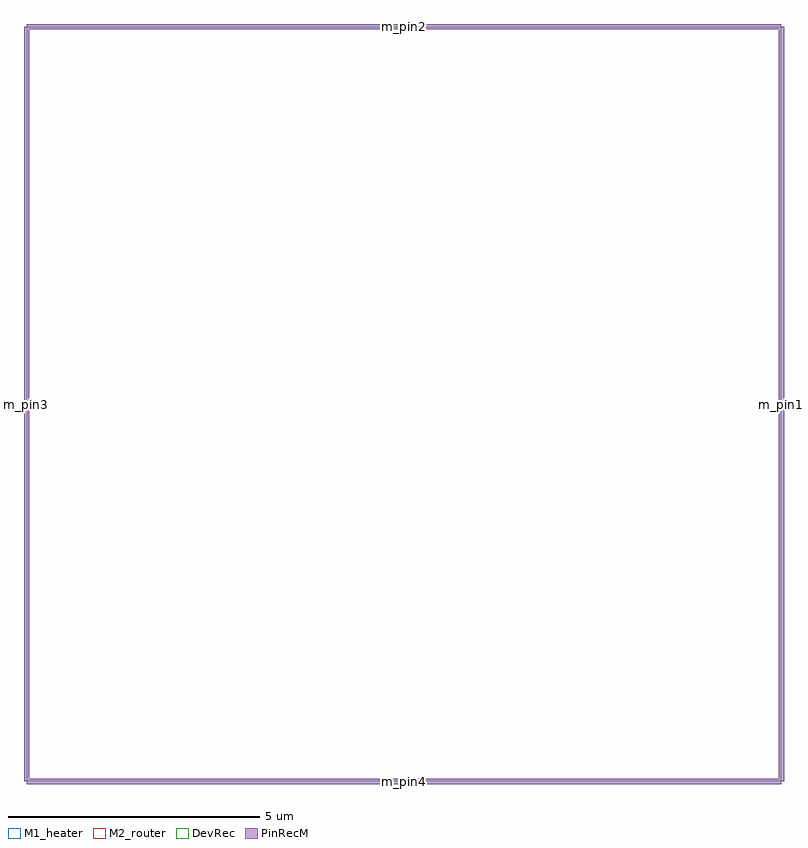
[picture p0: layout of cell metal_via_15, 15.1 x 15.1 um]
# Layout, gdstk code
import gdstk
lib = gdstk.Library(unit=1e-6, precision=1e-09)
def R(c, l, rs):  # rectangles x0, y0, x1, y1
    for r in rs: c.add(gdstk.rectangle(r[:2], r[2:], *l))
PinRecM = (1, 11)
M1_heater = (11, 0)
M2_router = (12, 0)
DevRec = (68, 0)

metal_via_15 = lib.new_cell('metal_via_15')
R(metal_via_15, M1_heater, [(-7.5,-7.5,7.5,7.5)])
R(metal_via_15, M2_router, [(-7.5,-7.5,7.5,7.5)])
R(metal_via_15, DevRec, [(-7.5,-7.5,7.5,7.5)])
metal_via_15.add(gdstk.FlexPath([(0,7.45),(0,7.55)], 15, ends="flush", simple_path=True, layer=1, datatype=11))  # PinRecM
metal_via_15.add(gdstk.FlexPath([(0,-7.45),(0,-7.55)], 15, ends="flush", simple_path=True, layer=1, datatype=11))  # PinRecM
metal_via_15.add(gdstk.FlexPath([(-7.45,0),(-7.55,0)], 15, ends="flush", simple_path=True, layer=1, datatype=11))  # PinRecM
metal_via_15.add(gdstk.FlexPath([(7.45,0),(7.55,0)], 15, ends="flush", simple_path=True, layer=1, datatype=11))  # PinRecM
metal_via_15.add(gdstk.Label('m_pin2', (0,7.5), layer=1, texttype=11))
metal_via_15.add(gdstk.Label('m_pin4', (0,-7.5), layer=1, texttype=11))
metal_via_15.add(gdstk.Label('m_pin3', (-7.5,0), layer=1, texttype=11))
metal_via_15.add(gdstk.Label('m_pin1', (7.5,0), layer=1, texttype=11))

lib.write_gds('metal_via_15.gds')
